VERSION 5.8 ;
BUSBITCHARS "[]" ;
DIVIDERCHAR "/" ;
CLEARANCEMEASURE EUCLIDEAN ;

SITE coresite_DH_P
    SIZE 0.0450 BY 0.2880 ;
    CLASS CORE ;
    SYMMETRY X Y ;
END coresite_DH_P

SITE coresite_DH_N
    SIZE 0.0450 BY 0.2880 ;
    CLASS CORE ;
    SYMMETRY X Y ;
END coresite_DH_N

SITE coresite
    SIZE 0.0450 BY 0.1440 ;
    CLASS CORE ;
    SYMMETRY X Y ;
END coresite

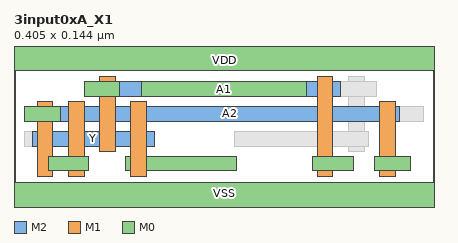
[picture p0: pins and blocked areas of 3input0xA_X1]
MACRO 3input0xA_X1
  CLASS CORE ;
  ORIGIN 0 0 ;
  FOREIGN 3input0xA_X1 0 0 ;
  SIZE 0.4050 BY 0.1440 ;
  SYMMETRY X Y ;
  SITE coresite ;
  PIN Y
    DIRECTION OUTPUT ;
    USE SIGNAL ;
    PORT
      LAYER M2 ;
        RECT 0.0180 0.0670 0.1350 0.0530 ;
      LAYER M1 ;
        RECT 0.0225 0.0960 0.0375 0.0240 ;
        RECT 0.1125 0.0960 0.1275 0.0240 ;
      LAYER M0 ;
        RECT 0.0105 0.0910 0.0450 0.0770 ;
        RECT 0.1080 0.0430 0.2145 0.0290 ;
    END
  END Y
  PIN A2
    DIRECTION INPUT ;
    USE SIGNAL ;
    PORT
      LAYER M2 ;
        RECT 0.0450 0.0910 0.3720 0.0770 ;
      LAYER M1 ;
        RECT 0.0525 0.0960 0.0675 0.0240 ;
        RECT 0.3525 0.0960 0.3675 0.0240 ;
      LAYER M0 ;
        RECT 0.0330 0.0430 0.0720 0.0290 ;
        RECT 0.3480 0.0430 0.3825 0.0290 ;
    END
  END A2
  PIN A3
    DIRECTION INPUT ;
    USE SIGNAL ;
    PORT
      LAYER M2 ;
        RECT 0.0780 0.1150 0.3150 0.1010 ;
      LAYER M1 ;
        RECT 0.0825 0.1200 0.0975 0.0480 ;
        RECT 0.2925 0.1200 0.3075 0.0240 ;
      LAYER M0 ;
        RECT 0.0675 0.1150 0.1020 0.1010 ;
        RECT 0.2880 0.0430 0.3270 0.0290 ;
    END
  END A3
  PIN A1
    DIRECTION INPUT ;
    USE SIGNAL ;
    PORT
      LAYER M0 ;
        RECT 0.1230 0.1150 0.2820 0.1010 ;
    END
  END A1
  PIN VDD
    DIRECTION INOUT ;
    USE POWER ;
    SHAPE ABUTMENT ;
    PORT
      LAYER M0 ;
        RECT 0.0000 0.1260 0.4050 0.1620 ;
    END
  END VDD
  PIN VSS
    DIRECTION INOUT ;
    USE GROUND ;
    SHAPE ABUTMENT ;
    PORT
      LAYER M0 ;
        RECT 0.0000 -0.0180 0.4050 0.0180 ;
    END
  END VSS
  OBS
      LAYER V1 ;
        RECT 0.0830 0.1010 0.0970 0.1150 ;
        RECT 0.2930 0.1010 0.3070 0.1150 ;
        RECT 0.0230 0.0530 0.0370 0.0670 ;
        RECT 0.1130 0.0530 0.1270 0.0670 ;
        RECT 0.0530 0.0770 0.0670 0.0910 ;
        RECT 0.3530 0.0770 0.3670 0.0910 ;
      LAYER V0 ;
        RECT 0.3230 0.1010 0.3370 0.1150 ;
        RECT 0.3230 0.0530 0.3370 0.0670 ;
        RECT 0.0830 0.1010 0.0970 0.1150 ;
        RECT 0.2930 0.0290 0.3070 0.0430 ;
        RECT 0.0230 0.0770 0.0370 0.0910 ;
        RECT 0.1130 0.0290 0.1270 0.0430 ;
        RECT 0.0530 0.0290 0.0670 0.0430 ;
        RECT 0.3530 0.0290 0.3670 0.0430 ;
      LAYER M1 ;
        RECT 0.3225 0.1200 0.3375 0.0480 ;
      LAYER M0 ;
        RECT 0.0105 0.0530 0.1245 0.0670 ;
        RECT 0.2130 0.0530 0.3420 0.0670 ;
        RECT 0.1005 0.0770 0.2145 0.0910 ;
        RECT 0.2805 0.0770 0.3945 0.0910 ;
        RECT 0.3150 0.1010 0.3495 0.1150 ;
  END
END 3input0xA_X1

END LIBRARY
